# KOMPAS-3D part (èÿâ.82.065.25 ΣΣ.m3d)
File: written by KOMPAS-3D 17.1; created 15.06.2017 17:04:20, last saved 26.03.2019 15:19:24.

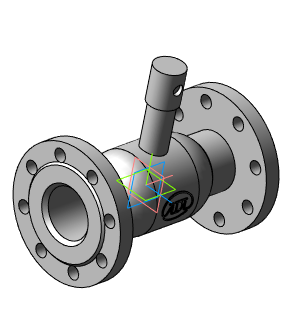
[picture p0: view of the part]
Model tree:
1. Операция без истории:2  (labels: Сталь 20  ГОСТ 1050-88)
